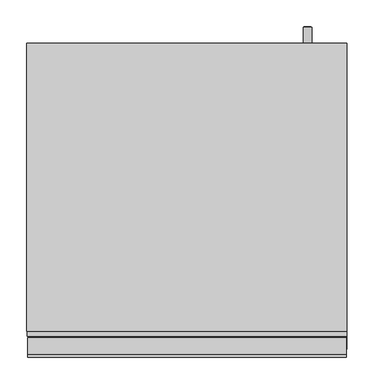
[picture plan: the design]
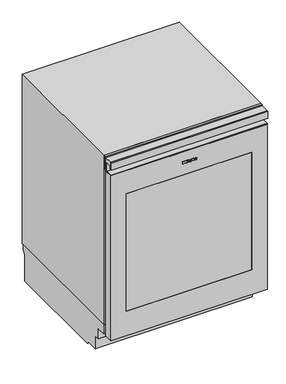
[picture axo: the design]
"""IFC4 building model written with IfcOpenShell, lengths in millimetres: proxy geometry."""

from ifc_helpers import new_model, si_unit, point, frame, frame_2d, origin, origin_with_axes, place, context, project, spatial, polyline, circle_curve, ellipse_curve, trimmed, segment, composite_curve, outline, extrude, faceted_brep, source, transform, mapped, element, save
from ifc_brep_helpers import plane_surface, cylinder_surface, revolved_surface, extruded_surface, advanced_brep


def specialty_equipment_ec8dbac2(model_context):
    return source(origin(), model_context, "Body", "SolidModel", [
        extrude(outline(polyline([(722.339, -25.038), (722.339, -23.949), (716.318, -23.949), (716.318, -25.038), (714.806, -25.038), (714.806, -21.078), (716.318, -21.078), (716.318, -22.158), (720.1401247, -22.158), (714.806, -18.135), (720.2462223, -14.094), (716.318, -14.094), (716.318, -15.201), (714.806, -15.201), (714.806, -8.019), (716.318, -8.019), (716.318, -9.162), (722.339, -9.162), (722.339, -8.019), (723.806, -8.019), (723.806, -13.5), (720.431, -16.128), (723.806, -18.765), (723.806, -25.038), (722.339, -25.038)])), frame((0.0, -1.0, 0.0), z_axis=(0.0, 1.0, 0.0), x_axis=(0.0, 0.0, 1.0)), (0.0, 0.0, 1.0), 1.0),
        extrude(outline(polyline([(722.339, 11.484), (722.339, 12.564), (716.318, 12.564), (716.318, 11.484), (714.806, 11.484), (714.806, 18.783), (716.318, 18.783), (716.318, 17.676), (723.806, 17.676), (723.806, 11.484), (722.339, 11.484)])), frame((0.0, -1.0, 0.0), z_axis=(0.0, 1.0, 0.0), x_axis=(0.0, 0.0, 1.0)), (0.0, 0.0, 1.0), 1.0),
        extrude(outline(polyline([(723.275, -4.878), (721.817, -4.194), (723.239, -1.143), (724.697, -1.818), (723.275, -4.878)])), frame((0.0, -1.0, 0.0), z_axis=(0.0, 1.0, 0.0), x_axis=(0.0, 0.0, 1.0)), (0.0, 0.0, 1.0), 1.0),
        extrude(outline(polyline([(721.619, -7.101), (720.008, -7.101), (720.008, -6.03), (716.318, -6.03), (716.318, -7.101), (714.806, -7.101), (714.806, 0.0), (716.318, 0.0), (716.318, -1.044), (721.619, -1.044), (721.619, -7.101)])), frame((0.0, -1.0, 0.0), z_axis=(0.0, 1.0, 0.0), x_axis=(0.0, 0.0, 1.0)), (0.0, 0.0, 1.0), 1.0),
        advanced_brep(
        [(4.959, -1.0, 716.939), (4.959, -1.0, 717.848), (10.98, -1.0, 717.848), (0.504, -1.0, 717.848), (2.979, -1.0, 714.806), (10.827, -1.0, 716.939), (8.109, -1.0, 716.939), (5.967, -1.0, 715.931), (4.959, -1.0, 719.0), (4.959, -1.0, 719.981), (6.498, -1.0, 719.981), (6.498, -1.0, 719.0), (4.959, 0.0, 716.939), (5.967, 0.0, 715.931), (8.109, 0.0, 716.939), (10.827, 0.0, 716.939), (2.979, 0.0, 714.806), (0.504, 0.0, 717.848), (10.98, 0.0, 717.848), (4.959, 0.0, 717.848), (4.959, 0.0, 719.0), (6.498, 0.0, 719.0), (6.498, 0.0, 719.981), (4.959, 0.0, 719.981)],
        [
            (0, 1),
            (1, 2),
            (2, 3, ellipse_curve(frame((5.742, -1.0, 717.848), z_axis=(0.0, -1.0, 0.0), x_axis=(-1.0, 0.0, 0.0)), 5.238, 4.329)),
            (3, 4, circle_curve(frame((3.9870491, -1.0, 718.154), z_axis=(0.0, -1.0, 0.0), x_axis=(0.0, 0.0, -1.0)), 3.4964649)),
            (4, 5, circle_curve(frame((5.6371428, -1.0, 720.53), z_axis=(0.0, -1.0, 0.0), x_axis=(0.0, 0.0, -1.0)), 6.3110933)),
            (5, 6),
            (6, 7, circle_curve(frame((6.4069412, -1.0, 717.776), z_axis=(0.0, 1.0, 0.0), x_axis=(0.0, 0.0, -1.0)), 1.896727)),
            (7, 0, circle_curve(frame((5.967, -1.0, 716.939), z_axis=(0.0, 1.0, 0.0), x_axis=(0.0, 0.0, -1.0)), 1.008)),
            (8, 9),
            (9, 10, circle_curve(frame((5.7285, -1.0, 719.981), z_axis=(0.0, 1.0, 0.0), x_axis=(0.0, 0.0, -1.0)), 0.7695)),
            (10, 11),
            (11, 8),
            (12, 13, circle_curve(frame((5.967, 0.0, 716.939), z_axis=(0.0, -1.0, 0.0), x_axis=(0.0, 0.0, -1.0)), 1.008)),
            (13, 14, circle_curve(frame((6.4069412, 0.0, 717.776), z_axis=(0.0, -1.0, 0.0), x_axis=(0.0, 0.0, -1.0)), 1.896727)),
            (14, 15),
            (15, 16, circle_curve(frame((5.6371428, 0.0, 720.53), z_axis=(0.0, 1.0, 0.0), x_axis=(0.0, 0.0, -1.0)), 6.3110933)),
            (16, 17, circle_curve(frame((3.9870491, 0.0, 718.154), z_axis=(0.0, 1.0, 0.0), x_axis=(0.0, 0.0, -1.0)), 3.4964649)),
            (17, 18, ellipse_curve(frame((5.742, 0.0, 717.848), z_axis=(0.0, 1.0, 0.0), x_axis=(-1.0, 0.0, 0.0)), 5.238, 4.329)),
            (18, 19),
            (19, 12),
            (20, 21),
            (21, 22),
            (22, 23, circle_curve(frame((5.7285, 0.0, 719.981), z_axis=(0.0, -1.0, 0.0), x_axis=(0.0, 0.0, -1.0)), 0.7695)),
            (23, 20),
            (0, 12),
            (19, 1),
            (18, 2),
            (5, 15),
            (14, 6),
            (17, 3),
            (13, 7),
            (16, 4),
            (8, 20),
            (23, 9),
            (22, 10),
            (21, 11),
        ],
        [
            plane_surface(frame((4.959, -1.0, 717.848), z_axis=(0.0, -1.0, 0.0), x_axis=(0.0, 0.0, 1.0))),
            plane_surface(frame((4.959, 0.0, 717.848), z_axis=(0.0, 1.0, 0.0), x_axis=(0.0, 0.0, -1.0))),
            plane_surface(frame((4.959, -1.0, 716.939), z_axis=(1.0, 0.0, 0.0), x_axis=(0.0, 1.0, 0.0))),
            plane_surface(frame((4.959, -1.0, 717.848), z_axis=(0.0, 0.0, -1.0), x_axis=(0.0, 1.0, 0.0))),
            plane_surface(frame((10.827, -1.0, 716.939), z_axis=(0.0, 0.0, 1.0), x_axis=(0.0, 1.0, 0.0))),
            extruded_surface(trimmed(ellipse_curve(frame((5.742, 1.0, 717.848), z_axis=(0.0, -1.0, 0.0), x_axis=(-1.0, 0.0, 0.0)), 5.238, 4.329), [point((10.98, 1.0, 717.848))], [point((0.504, 1.0, 717.848))], True, "CARTESIAN"), (0.0, -1.0, 0.0), 1.0),
            revolved_surface(polyline([(6.4069412, 0.0, 715.8792729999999), (6.4069412, -1.0, 715.8792729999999)]), (6.4069412, 0.0, 717.776), (0.0, 1.0, 0.0)),
            revolved_surface(polyline([(5.967, 0.0, 715.9309999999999), (5.967, -1.0, 715.9309999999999)]), (5.967, 0.0, 716.939), (0.0, 1.0, 0.0)),
            cylinder_surface(frame((3.9870491, 0.0, 718.154), z_axis=(0.0, -1.0, 0.0), x_axis=(0.0, 0.0, -1.0)), 3.4964649),
            cylinder_surface(frame((5.6371428, 0.0, 720.53), z_axis=(0.0, -1.0, 0.0), x_axis=(0.0, 0.0, -1.0)), 6.3110933),
            plane_surface(frame((4.959, -1.0, 719.0), z_axis=(1.0, 0.0, 0.0), x_axis=(0.0, 1.0, 0.0))),
            revolved_surface(polyline([(5.7285, 0.0, 719.2115), (5.7285, -1.0, 719.2115)]), (5.7285, 0.0, 719.981), (0.0, 1.0, 0.0)),
            plane_surface(frame((6.498, -1.0, 719.981), z_axis=(-1.0, 0.0, 0.0), x_axis=(0.0, 1.0, 0.0))),
            plane_surface(frame((6.498, -1.0, 719.0), z_axis=(0.0, 0.0, 1.0), x_axis=(0.0, 1.0, 0.0))),
        ],
        [
            (0, [[1, 2, 3, 4, 5, 6, 7, 8], [9, 10, 11, 12]]),
            (1, [[13, 14, 15, 16, 17, 18, 19, 20], [21, 22, 23, 24]]),
            (2, [[-1, 25, -20, 26]]),
            (3, [[-2, -26, -19, 27]]),
            (4, [[-6, 28, -15, 29]]),
            (5, [[-3, -27, -18, 30]]),
            (6, [[-7, -29, -14, 31]]),
            (7, [[-8, -31, -13, -25]]),
            (8, [[-4, -30, -17, 32]]),
            (9, [[-5, -32, -16, -28]]),
            (10, [[-9, 33, -24, 34]]),
            (11, [[-10, -34, -23, 35]]),
            (12, [[-11, -35, -22, 36]]),
            (13, [[-12, -36, -21, -33]]),
        ],
    ),
        advanced_brep(
        [(23.742, -1.0, 716.939), (23.742, -1.0, 717.848), (29.763, -1.0, 717.848), (19.287, -1.0, 717.848), (21.762, -1.0, 714.806), (29.61, -1.0, 716.939), (26.892, -1.0, 716.939), (24.75, -1.0, 715.931), (23.742, -1.0, 719.0), (23.742, -1.0, 719.981), (25.281, -1.0, 719.981), (25.281, -1.0, 719.0), (23.742, 0.0, 716.939), (24.75, 0.0, 715.931), (26.892, 0.0, 716.939), (29.61, 0.0, 716.939), (21.762, 0.0, 714.806), (19.287, 0.0, 717.848), (29.763, 0.0, 717.848), (23.742, 0.0, 717.848), (23.742, 0.0, 719.0), (25.281, 0.0, 719.0), (25.281, 0.0, 719.981), (23.742, 0.0, 719.981)],
        [
            (0, 1),
            (1, 2),
            (2, 3, ellipse_curve(frame((24.525, -1.0, 717.848), z_axis=(0.0, -1.0, 0.0), x_axis=(-1.0, 0.0, 0.0)), 5.238, 4.329)),
            (3, 4, circle_curve(frame((22.7700491, -1.0, 718.154), z_axis=(0.0, -1.0, 0.0), x_axis=(0.0, 0.0, -1.0)), 3.4964649)),
            (4, 5, circle_curve(frame((24.4201428, -1.0, 720.53), z_axis=(0.0, -1.0, 0.0), x_axis=(0.0, 0.0, -1.0)), 6.3110933)),
            (5, 6),
            (6, 7, circle_curve(frame((25.1899412, -1.0, 717.776), z_axis=(0.0, 1.0, 0.0), x_axis=(0.0, 0.0, -1.0)), 1.896727)),
            (7, 0, circle_curve(frame((24.75, -1.0, 716.939), z_axis=(0.0, 1.0, 0.0), x_axis=(0.0, 0.0, -1.0)), 1.008)),
            (8, 9),
            (9, 10, circle_curve(frame((24.5115, -1.0, 719.981), z_axis=(0.0, 1.0, 0.0), x_axis=(0.0, 0.0, -1.0)), 0.7695)),
            (10, 11),
            (11, 8),
            (12, 13, circle_curve(frame((24.75, 0.0, 716.939), z_axis=(0.0, -1.0, 0.0), x_axis=(0.0, 0.0, -1.0)), 1.008)),
            (13, 14, circle_curve(frame((25.1899412, 0.0, 717.776), z_axis=(0.0, -1.0, 0.0), x_axis=(0.0, 0.0, -1.0)), 1.896727)),
            (14, 15),
            (15, 16, circle_curve(frame((24.4201428, 0.0, 720.53), z_axis=(0.0, 1.0, 0.0), x_axis=(0.0, 0.0, -1.0)), 6.3110933)),
            (16, 17, circle_curve(frame((22.7700491, 0.0, 718.154), z_axis=(0.0, 1.0, 0.0), x_axis=(0.0, 0.0, -1.0)), 3.4964649)),
            (17, 18, ellipse_curve(frame((24.525, 0.0, 717.848), z_axis=(0.0, 1.0, 0.0), x_axis=(-1.0, 0.0, 0.0)), 5.238, 4.329)),
            (18, 19),
            (19, 12),
            (20, 21),
            (21, 22),
            (22, 23, circle_curve(frame((24.5115, 0.0, 719.981), z_axis=(0.0, -1.0, 0.0), x_axis=(0.0, 0.0, -1.0)), 0.7695)),
            (23, 20),
            (0, 12),
            (19, 1),
            (18, 2),
            (5, 15),
            (14, 6),
            (17, 3),
            (13, 7),
            (16, 4),
            (8, 20),
            (23, 9),
            (22, 10),
            (21, 11),
        ],
        [
            plane_surface(frame((23.742, -1.0, 717.848), z_axis=(0.0, -1.0, 0.0), x_axis=(0.0, 0.0, 1.0))),
            plane_surface(frame((23.742, 0.0, 717.848), z_axis=(0.0, 1.0, 0.0), x_axis=(0.0, 0.0, -1.0))),
            plane_surface(frame((23.742, -1.0, 716.939), z_axis=(1.0, 0.0, 0.0), x_axis=(0.0, 1.0, 0.0))),
            plane_surface(frame((23.742, -1.0, 717.848), z_axis=(0.0, 0.0, -1.0), x_axis=(0.0, 1.0, 0.0))),
            plane_surface(frame((29.61, -1.0, 716.939), z_axis=(0.0, 0.0, 1.0), x_axis=(0.0, 1.0, 0.0))),
            extruded_surface(trimmed(ellipse_curve(frame((24.525, 1.0, 717.848), z_axis=(0.0, -1.0, 0.0), x_axis=(-1.0, 0.0, 0.0)), 5.238, 4.329), [point((29.763, 1.0, 717.848))], [point((19.287, 1.0, 717.848))], True, "CARTESIAN"), (0.0, -1.0, 0.0), 1.0),
            revolved_surface(polyline([(25.1899412, 0.0, 715.8792729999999), (25.1899412, -1.0, 715.8792729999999)]), (25.1899412, 0.0, 717.776), (0.0, 1.0, 0.0)),
            revolved_surface(polyline([(24.75, 0.0, 715.9309999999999), (24.75, -1.0, 715.9309999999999)]), (24.75, 0.0, 716.939), (0.0, 1.0, 0.0)),
            cylinder_surface(frame((22.7700491, 0.0, 718.154), z_axis=(0.0, -1.0, 0.0), x_axis=(0.0, 0.0, -1.0)), 3.4964649),
            cylinder_surface(frame((24.4201428, 0.0, 720.53), z_axis=(0.0, -1.0, 0.0), x_axis=(0.0, 0.0, -1.0)), 6.3110933),
            plane_surface(frame((23.742, -1.0, 719.0), z_axis=(1.0, 0.0, 0.0), x_axis=(0.0, 1.0, 0.0))),
            revolved_surface(polyline([(24.5115, 0.0, 719.2115), (24.5115, -1.0, 719.2115)]), (24.5115, 0.0, 719.981), (0.0, 1.0, 0.0)),
            plane_surface(frame((25.281, -1.0, 719.981), z_axis=(-1.0, 0.0, 0.0), x_axis=(0.0, 1.0, 0.0))),
            plane_surface(frame((25.281, -1.0, 719.0), z_axis=(0.0, 0.0, 1.0), x_axis=(0.0, 1.0, 0.0))),
        ],
        [
            (0, [[1, 2, 3, 4, 5, 6, 7, 8], [9, 10, 11, 12]]),
            (1, [[13, 14, 15, 16, 17, 18, 19, 20], [21, 22, 23, 24]]),
            (2, [[-1, 25, -20, 26]]),
            (3, [[-2, -26, -19, 27]]),
            (4, [[-6, 28, -15, 29]]),
            (5, [[-3, -27, -18, 30]]),
            (6, [[-7, -29, -14, 31]]),
            (7, [[-8, -31, -13, -25]]),
            (8, [[-4, -30, -17, 32]]),
            (9, [[-5, -32, -16, -28]]),
            (10, [[-9, 33, -24, 34]]),
            (11, [[-10, -34, -23, 35]]),
            (12, [[-11, -35, -22, 36]]),
            (13, [[-12, -36, -21, -33]]),
        ],
    ),
        extrude(outline(polyline([(454.1556157, -89.367984), (454.1556157, -88.399984), (448.8036157, -88.399984), (448.8036157, -89.367984), (447.4596157, -89.367984), (447.4596157, -85.847984), (448.8036157, -85.847984), (448.8036157, -86.807984), (452.2067404, -86.807984), (447.4596157, -83.231984), (452.274838, -79.639984), (448.8036157, -79.639984), (448.8036157, -80.623984), (447.4596157, -80.623984), (447.4596157, -74.239984), (448.8036157, -74.239984), (448.8036157, -75.255984), (454.1556157, -75.255984), (454.1556157, -74.239984), (455.4596157, -74.239984), (455.4596157, -79.111984), (452.4596157, -81.447984), (455.4596157, -83.791984), (455.4596157, -89.367984), (454.1556157, -89.367984)])), frame((0.0, 50.0, 0.0), z_axis=(0.0, 1.0, 0.0), x_axis=(0.0, 0.0, 1.0)), (0.0, 0.0, 1.0), 1.0),
        extrude(outline(polyline([(454.1556157, -56.903984), (454.1556157, -55.943984), (448.8036157, -55.943984), (448.8036157, -56.903984), (447.4596157, -56.903984), (447.4596157, -50.415984), (448.8036157, -50.415984), (448.8036157, -51.399984), (455.4596157, -51.399984), (455.4596157, -56.903984), (454.1556157, -56.903984)])), frame((0.0, 50.0, 0.0), z_axis=(0.0, 1.0, 0.0), x_axis=(0.0, 0.0, 1.0)), (0.0, 0.0, 1.0), 1.0),
        extrude(outline(polyline([(454.9876157, -71.447984), (453.6916157, -70.839984), (454.9556157, -68.127984), (456.2516157, -68.727984), (454.9876157, -71.447984)])), frame((0.0, 50.0, 0.0), z_axis=(0.0, 1.0, 0.0), x_axis=(0.0, 0.0, 1.0)), (0.0, 0.0, 1.0), 1.0),
        extrude(outline(polyline([(453.5156157, -73.423984), (452.0836157, -73.423984), (452.0836157, -72.471984), (448.8036157, -72.471984), (448.8036157, -73.423984), (447.4596157, -73.423984), (447.4596157, -67.111984), (448.8036157, -67.111984), (448.8036157, -68.039984), (453.5156157, -68.039984), (453.5156157, -73.423984)])), frame((0.0, 50.0, 0.0), z_axis=(0.0, 1.0, 0.0), x_axis=(0.0, 0.0, 1.0)), (0.0, 0.0, 1.0), 1.0),
        advanced_brep(
        [(-62.703984, 50.0, 449.3556157), (-62.703984, 50.0, 450.1636157), (-57.351984, 50.0, 450.1636157), (-66.663984, 50.0, 450.1636157), (-64.463984, 50.0, 447.4596157), (-57.487984, 50.0, 449.3556157), (-59.903984, 50.0, 449.3556157), (-61.807984, 50.0, 448.4596157), (-62.703984, 50.0, 451.1876157), (-62.703984, 50.0, 452.0596157), (-61.335984, 50.0, 452.0596157), (-61.335984, 50.0, 451.1876157), (-62.703984, 51.0, 449.3556157), (-61.807984, 51.0, 448.4596157), (-59.903984, 51.0, 449.3556157), (-57.487984, 51.0, 449.3556157), (-64.463984, 51.0, 447.4596157), (-66.663984, 51.0, 450.1636157), (-57.351984, 51.0, 450.1636157), (-62.703984, 51.0, 450.1636157), (-62.703984, 51.0, 451.1876157), (-61.335984, 51.0, 451.1876157), (-61.335984, 51.0, 452.0596157), (-62.703984, 51.0, 452.0596157)],
        [
            (0, 1),
            (1, 2),
            (2, 3, ellipse_curve(frame((-62.007984, 50.0, 450.1636157), z_axis=(0.0, -1.0, 0.0), x_axis=(-1.0, 0.0, 0.0)), 4.656, 3.848)),
            (3, 4, circle_curve(frame((-63.5679404, 50.0, 450.4356157), z_axis=(0.0, -1.0, 0.0), x_axis=(0.0, 0.0, -1.0)), 3.1079688)),
            (4, 5, circle_curve(frame((-62.1011904, 50.0, 452.5476157), z_axis=(0.0, -1.0, 0.0), x_axis=(0.0, 0.0, -1.0)), 5.6098607)),
            (5, 6),
            (6, 7, circle_curve(frame((-61.4169252, 50.0, 450.0996157), z_axis=(0.0, 1.0, 0.0), x_axis=(0.0, 0.0, -1.0)), 1.6859795)),
            (7, 0, circle_curve(frame((-61.807984, 50.0, 449.3556157), z_axis=(0.0, 1.0, 0.0), x_axis=(0.0, 0.0, -1.0)), 0.896)),
            (8, 9),
            (9, 10, circle_curve(frame((-62.019984, 50.0, 452.0596157), z_axis=(0.0, 1.0, 0.0), x_axis=(0.0, 0.0, -1.0)), 0.684)),
            (10, 11),
            (11, 8),
            (12, 13, circle_curve(frame((-61.807984, 51.0, 449.3556157), z_axis=(0.0, -1.0, 0.0), x_axis=(0.0, 0.0, -1.0)), 0.896)),
            (13, 14, circle_curve(frame((-61.4169252, 51.0, 450.0996157), z_axis=(0.0, -1.0, 0.0), x_axis=(0.0, 0.0, -1.0)), 1.6859795)),
            (14, 15),
            (15, 16, circle_curve(frame((-62.1011904, 51.0, 452.5476157), z_axis=(0.0, 1.0, 0.0), x_axis=(0.0, 0.0, -1.0)), 5.6098607)),
            (16, 17, circle_curve(frame((-63.5679404, 51.0, 450.4356157), z_axis=(0.0, 1.0, 0.0), x_axis=(0.0, 0.0, -1.0)), 3.1079688)),
            (17, 18, ellipse_curve(frame((-62.007984, 51.0, 450.1636157), z_axis=(0.0, 1.0, 0.0), x_axis=(-1.0, 0.0, 0.0)), 4.656, 3.848)),
            (18, 19),
            (19, 12),
            (20, 21),
            (21, 22),
            (22, 23, circle_curve(frame((-62.019984, 51.0, 452.0596157), z_axis=(0.0, -1.0, 0.0), x_axis=(0.0, 0.0, -1.0)), 0.684)),
            (23, 20),
            (0, 12),
            (19, 1),
            (18, 2),
            (5, 15),
            (14, 6),
            (17, 3),
            (13, 7),
            (16, 4),
            (8, 20),
            (23, 9),
            (22, 10),
            (21, 11),
        ],
        [
            plane_surface(frame((-62.703984, 50.0, 450.1636157), z_axis=(0.0, -1.0, 0.0), x_axis=(0.0, 0.0, 1.0))),
            plane_surface(frame((-62.703984, 51.0, 450.1636157), z_axis=(0.0, 1.0, 0.0), x_axis=(0.0, 0.0, -1.0))),
            plane_surface(frame((-62.703984, 50.0, 449.3556157), z_axis=(1.0, 0.0, 0.0), x_axis=(0.0, 1.0, 0.0))),
            plane_surface(frame((-62.703984, 50.0, 450.1636157), z_axis=(0.0, 0.0, -1.0), x_axis=(0.0, 1.0, 0.0))),
            plane_surface(frame((-57.487984, 50.0, 449.3556157), z_axis=(0.0, 0.0, 1.0), x_axis=(0.0, 1.0, 0.0))),
            extruded_surface(trimmed(ellipse_curve(frame((-62.007984, 52.0, 450.1636157), z_axis=(0.0, -1.0, 0.0), x_axis=(-1.0, 0.0, 0.0)), 4.656, 3.848), [point((-57.351984, 52.0, 450.1636157))], [point((-66.663984, 52.0, 450.1636157))], True, "CARTESIAN"), (0.0, -1.0, 0.0), 1.0),
            revolved_surface(polyline([(-61.4169252, 51.0, 448.41363620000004), (-61.4169252, 50.0, 448.41363620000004)]), (-61.4169252, 51.0, 450.0996157), (0.0, 1.0, 0.0)),
            revolved_surface(polyline([(-61.807984, 51.0, 448.4596157), (-61.807984, 50.0, 448.4596157)]), (-61.807984, 51.0, 449.3556157), (0.0, 1.0, 0.0)),
            cylinder_surface(frame((-63.5679404, 51.0, 450.4356157), z_axis=(0.0, -1.0, 0.0), x_axis=(0.0, 0.0, -1.0)), 3.1079688),
            cylinder_surface(frame((-62.1011904, 51.0, 452.5476157), z_axis=(0.0, -1.0, 0.0), x_axis=(0.0, 0.0, -1.0)), 5.6098607),
            plane_surface(frame((-62.703984, 50.0, 451.1876157), z_axis=(1.0, 0.0, 0.0), x_axis=(0.0, 1.0, 0.0))),
            revolved_surface(polyline([(-62.019984, 51.0, 451.37561569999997), (-62.019984, 50.0, 451.37561569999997)]), (-62.019984, 51.0, 452.0596157), (0.0, 1.0, 0.0)),
            plane_surface(frame((-61.335984, 50.0, 452.0596157), z_axis=(-1.0, 0.0, 0.0), x_axis=(0.0, 1.0, 0.0))),
            plane_surface(frame((-61.335984, 50.0, 451.1876157), z_axis=(0.0, 0.0, 1.0), x_axis=(0.0, 1.0, 0.0))),
        ],
        [
            (0, [[1, 2, 3, 4, 5, 6, 7, 8], [9, 10, 11, 12]]),
            (1, [[13, 14, 15, 16, 17, 18, 19, 20], [21, 22, 23, 24]]),
            (2, [[-1, 25, -20, 26]]),
            (3, [[-2, -26, -19, 27]]),
            (4, [[-6, 28, -15, 29]]),
            (5, [[-3, -27, -18, 30]]),
            (6, [[-7, -29, -14, 31]]),
            (7, [[-8, -31, -13, -25]]),
            (8, [[-4, -30, -17, 32]]),
            (9, [[-5, -32, -16, -28]]),
            (10, [[-9, 33, -24, 34]]),
            (11, [[-10, -34, -23, 35]]),
            (12, [[-11, -35, -22, 36]]),
            (13, [[-12, -36, -21, -33]]),
        ],
    ),
        advanced_brep(
        [(-46.007984, 50.0, 449.3556157), (-46.007984, 50.0, 450.1636157), (-40.655984, 50.0, 450.1636157), (-49.967984, 50.0, 450.1636157), (-47.767984, 50.0, 447.4596157), (-40.791984, 50.0, 449.3556157), (-43.207984, 50.0, 449.3556157), (-45.111984, 50.0, 448.4596157), (-46.007984, 50.0, 451.1876157), (-46.007984, 50.0, 452.0596157), (-44.639984, 50.0, 452.0596157), (-44.639984, 50.0, 451.1876157), (-46.007984, 51.0, 449.3556157), (-45.111984, 51.0, 448.4596157), (-43.207984, 51.0, 449.3556157), (-40.791984, 51.0, 449.3556157), (-47.767984, 51.0, 447.4596157), (-49.967984, 51.0, 450.1636157), (-40.655984, 51.0, 450.1636157), (-46.007984, 51.0, 450.1636157), (-46.007984, 51.0, 451.1876157), (-44.639984, 51.0, 451.1876157), (-44.639984, 51.0, 452.0596157), (-46.007984, 51.0, 452.0596157)],
        [
            (0, 1),
            (1, 2),
            (2, 3, ellipse_curve(frame((-45.311984, 50.0, 450.1636157), z_axis=(0.0, -1.0, 0.0), x_axis=(-1.0, 0.0, 0.0)), 4.656, 3.848)),
            (3, 4, circle_curve(frame((-46.8719404, 50.0, 450.4356157), z_axis=(0.0, -1.0, 0.0), x_axis=(0.0, 0.0, -1.0)), 3.1079688)),
            (4, 5, circle_curve(frame((-45.4051904, 50.0, 452.5476157), z_axis=(0.0, -1.0, 0.0), x_axis=(0.0, 0.0, -1.0)), 5.6098607)),
            (5, 6),
            (6, 7, circle_curve(frame((-44.7209252, 50.0, 450.0996157), z_axis=(0.0, 1.0, 0.0), x_axis=(0.0, 0.0, -1.0)), 1.6859795)),
            (7, 0, circle_curve(frame((-45.111984, 50.0, 449.3556157), z_axis=(0.0, 1.0, 0.0), x_axis=(0.0, 0.0, -1.0)), 0.896)),
            (8, 9),
            (9, 10, circle_curve(frame((-45.323984, 50.0, 452.0596157), z_axis=(0.0, 1.0, 0.0), x_axis=(0.0, 0.0, -1.0)), 0.684)),
            (10, 11),
            (11, 8),
            (12, 13, circle_curve(frame((-45.111984, 51.0, 449.3556157), z_axis=(0.0, -1.0, 0.0), x_axis=(0.0, 0.0, -1.0)), 0.896)),
            (13, 14, circle_curve(frame((-44.7209252, 51.0, 450.0996157), z_axis=(0.0, -1.0, 0.0), x_axis=(0.0, 0.0, -1.0)), 1.6859795)),
            (14, 15),
            (15, 16, circle_curve(frame((-45.4051904, 51.0, 452.5476157), z_axis=(0.0, 1.0, 0.0), x_axis=(0.0, 0.0, -1.0)), 5.6098607)),
            (16, 17, circle_curve(frame((-46.8719404, 51.0, 450.4356157), z_axis=(0.0, 1.0, 0.0), x_axis=(0.0, 0.0, -1.0)), 3.1079688)),
            (17, 18, ellipse_curve(frame((-45.311984, 51.0, 450.1636157), z_axis=(0.0, 1.0, 0.0), x_axis=(-1.0, 0.0, 0.0)), 4.656, 3.848)),
            (18, 19),
            (19, 12),
            (20, 21),
            (21, 22),
            (22, 23, circle_curve(frame((-45.323984, 51.0, 452.0596157), z_axis=(0.0, -1.0, 0.0), x_axis=(0.0, 0.0, -1.0)), 0.684)),
            (23, 20),
            (0, 12),
            (19, 1),
            (18, 2),
            (5, 15),
            (14, 6),
            (17, 3),
            (13, 7),
            (16, 4),
            (8, 20),
            (23, 9),
            (22, 10),
            (21, 11),
        ],
        [
            plane_surface(frame((-46.007984, 50.0, 450.1636157), z_axis=(0.0, -1.0, 0.0), x_axis=(0.0, 0.0, 1.0))),
            plane_surface(frame((-46.007984, 51.0, 450.1636157), z_axis=(0.0, 1.0, 0.0), x_axis=(0.0, 0.0, -1.0))),
            plane_surface(frame((-46.007984, 50.0, 449.3556157), z_axis=(1.0, 0.0, 0.0), x_axis=(0.0, 1.0, 0.0))),
            plane_surface(frame((-46.007984, 50.0, 450.1636157), z_axis=(0.0, 0.0, -1.0), x_axis=(0.0, 1.0, 0.0))),
            plane_surface(frame((-40.791984, 50.0, 449.3556157), z_axis=(0.0, 0.0, 1.0), x_axis=(0.0, 1.0, 0.0))),
            extruded_surface(trimmed(ellipse_curve(frame((-45.311984, 52.0, 450.1636157), z_axis=(0.0, -1.0, 0.0), x_axis=(-1.0, 0.0, 0.0)), 4.656, 3.848), [point((-40.655984, 52.0, 450.1636157))], [point((-49.967984, 52.0, 450.1636157))], True, "CARTESIAN"), (0.0, -1.0, 0.0), 1.0),
            revolved_surface(polyline([(-44.7209252, 51.0, 448.41363620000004), (-44.7209252, 50.0, 448.41363620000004)]), (-44.7209252, 51.0, 450.0996157), (0.0, 1.0, 0.0)),
            revolved_surface(polyline([(-45.111984, 51.0, 448.4596157), (-45.111984, 50.0, 448.4596157)]), (-45.111984, 51.0, 449.3556157), (0.0, 1.0, 0.0)),
            cylinder_surface(frame((-46.8719404, 51.0, 450.4356157), z_axis=(0.0, -1.0, 0.0), x_axis=(0.0, 0.0, -1.0)), 3.1079688),
            cylinder_surface(frame((-45.4051904, 51.0, 452.5476157), z_axis=(0.0, -1.0, 0.0), x_axis=(0.0, 0.0, -1.0)), 5.6098607),
            plane_surface(frame((-46.007984, 50.0, 451.1876157), z_axis=(1.0, 0.0, 0.0), x_axis=(0.0, 1.0, 0.0))),
            revolved_surface(polyline([(-45.323984, 51.0, 451.37561569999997), (-45.323984, 50.0, 451.37561569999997)]), (-45.323984, 51.0, 452.0596157), (0.0, 1.0, 0.0)),
            plane_surface(frame((-44.639984, 50.0, 452.0596157), z_axis=(-1.0, 0.0, 0.0), x_axis=(0.0, 1.0, 0.0))),
            plane_surface(frame((-44.639984, 50.0, 451.1876157), z_axis=(0.0, 0.0, 1.0), x_axis=(0.0, 1.0, 0.0))),
        ],
        [
            (0, [[1, 2, 3, 4, 5, 6, 7, 8], [9, 10, 11, 12]]),
            (1, [[13, 14, 15, 16, 17, 18, 19, 20], [21, 22, 23, 24]]),
            (2, [[-1, 25, -20, 26]]),
            (3, [[-2, -26, -19, 27]]),
            (4, [[-6, 28, -15, 29]]),
            (5, [[-3, -27, -18, 30]]),
            (6, [[-7, -29, -14, 31]]),
            (7, [[-8, -31, -13, -25]]),
            (8, [[-4, -30, -17, 32]]),
            (9, [[-5, -32, -16, -28]]),
            (10, [[-9, 33, -24, 34]]),
            (11, [[-10, -34, -23, 35]]),
            (12, [[-11, -35, -22, 36]]),
            (13, [[-12, -36, -21, -33]]),
        ],
    ),
        extrude(outline(polyline([(238.8, -157.5), (243.5052612, -157.5), (247.5052612, -161.5), (247.5052612, -168.5), (243.5052612, -172.5), (238.8, -172.5), (238.8, -157.5)])), frame((0.0, 54.5000244, 0.0), z_axis=(0.0, 1.0, 0.0), x_axis=(0.0, 0.0, 1.0)), (0.0, 0.0, 1.0), 433.111792),
        extrude(outline(polyline([(238.8, -102.5), (243.5052612, -102.5), (247.5052612, -106.5), (247.5052612, -113.5), (243.5052612, -117.5), (238.8, -117.5), (238.8, -102.5)])), frame((0.0, 54.5000244, 0.0), z_axis=(0.0, 1.0, 0.0), x_axis=(0.0, 0.0, 1.0)), (0.0, 0.0, 1.0), 433.111792),
        extrude(outline(polyline([(238.8, 157.5), (238.8, 172.5), (243.5052612, 172.5), (247.5052612, 168.5), (247.5052612, 161.5), (243.5052612, 157.5), (238.8, 157.5)])), frame((0.0, 54.5000244, 0.0), z_axis=(0.0, 1.0, 0.0), x_axis=(0.0, 0.0, 1.0)), (0.0, 0.0, 1.0), 433.111792),
        extrude(outline(polyline([(238.8, 102.5), (238.8, 117.5), (243.5052612, 117.5), (247.5052612, 113.5), (247.5052612, 106.5), (243.5052612, 102.5), (238.8, 102.5)])), frame((0.0, 54.5000244, 0.0), z_axis=(0.0, 1.0, 0.0), x_axis=(0.0, 0.0, 1.0)), (0.0, 0.0, 1.0), 433.111792),
        extrude(outline(polyline([(238.8, -47.5), (243.5052612, -47.5), (247.5052612, -51.5), (247.5052612, -58.5), (243.5052612, -62.5), (238.8, -62.5), (238.8, -47.5)])), frame((0.0, 54.5000244, 0.0), z_axis=(0.0, 1.0, 0.0), x_axis=(0.0, 0.0, 1.0)), (0.0, 0.0, 1.0), 433.111792),
        extrude(outline(polyline([(238.8, 47.5), (238.8, 62.5), (243.5052612, 62.5), (247.5052612, 58.5), (247.5052612, 51.5), (243.5052612, 47.5), (238.8, 47.5)])), frame((0.0, 54.5000244, 0.0), z_axis=(0.0, 1.0, 0.0), x_axis=(0.0, 0.0, 1.0)), (0.0, 0.0, 1.0), 433.111792),
        extrude(outline(polyline([(238.8, 7.5), (243.5052612, 7.5), (247.5052612, 3.5), (247.5052612, -3.5), (243.5052612, -7.5), (238.8, -7.5), (238.8, 7.5)])), frame((0.0, 54.5000244, 0.0), z_axis=(0.0, 1.0, 0.0), x_axis=(0.0, 0.0, 1.0)), (0.0, 0.0, 1.0), 433.111792),
        extrude(outline(polyline([(238.5, 51.0000244), (-238.5, 51.0000244), (-238.5, 54.5000244), (238.5, 54.5000244), (238.5, 51.0000244)])), frame((0.0, 0.0, 146.0), z_axis=(0.0, 0.0, 1.0), x_axis=(1.0, 0.0, 0.0)), (0.0, 0.0, 1.0), 27.5),
        extrude(outline(polyline([(209.0, -226.9226475), (209.0, -238.5), (141.0206134, -238.5), (141.0206134, -216.8069153), (191.4790485, -216.8069153), (209.0, -226.9226475)])), frame((0.0, 54.5000244, 0.0), z_axis=(0.0, 1.0, 0.0), x_axis=(0.0, 0.0, 1.0)), (0.0, 0.0, 1.0), 308.1981801),
        extrude(outline(polyline([(209.0, 226.9226475), (191.4790485, 216.8069153), (141.0206134, 216.8069153), (141.0206134, 238.5), (209.0, 238.5), (209.0, 226.9226475)])), frame((0.0, 54.5000244, 0.0), z_axis=(0.0, 1.0, 0.0), x_axis=(0.0, 0.0, 1.0)), (0.0, 0.0, 1.0), 308.1981801),
        extrude(outline(polyline([(238.5, 51.0000244), (-238.5, 51.0000244), (-238.5, 54.5000244), (238.5, 54.5000244), (238.5, 51.0000244)])), frame((0.0, 0.0, 324.0), z_axis=(0.0, 0.0, 1.0), x_axis=(1.0, 0.0, 0.0)), (0.0, 0.0, 1.0), 27.5),
        extrude(outline(polyline([(618.2947388, -160.4764937), (623.0, -160.4764937), (627.0, -164.4764937), (627.0, -171.4764937), (623.0, -175.4764937), (618.2947388, -175.4764937), (618.2947388, -160.4764937)])), frame((0.0, 54.5000244, 0.0), z_axis=(0.0, 1.0, 0.0), x_axis=(0.0, 0.0, 1.0)), (0.0, 0.0, 1.0), 433.111792),
        extrude(outline(polyline([(618.2947388, -134.5453754), (623.0, -134.5453754), (627.0, -138.5453754), (627.0, -145.5453754), (623.0, -149.5453754), (618.2947388, -149.5453754), (618.2947388, -134.5453754)])), frame((0.0, 54.5000244, 0.0), z_axis=(0.0, 1.0, 0.0), x_axis=(0.0, 0.0, 1.0)), (0.0, 0.0, 1.0), 433.111792),
        extrude(outline(polyline([(618.2947388, -82.9166641), (623.0, -82.9166641), (627.0, -86.9166641), (627.0, -93.9166641), (623.0, -97.9166641), (618.2947388, -97.9166641), (618.2947388, -82.9166641)])), frame((0.0, 54.5000244, 0.0), z_axis=(0.0, 1.0, 0.0), x_axis=(0.0, 0.0, 1.0)), (0.0, 0.0, 1.0), 433.111792),
        extrude(outline(polyline([(618.2947388, -56.9855458), (623.0, -56.9855458), (627.0, -60.9855458), (627.0, -67.9855458), (623.0, -71.9855458), (618.2947388, -71.9855458), (618.2947388, -56.9855458)])), frame((0.0, 54.5000244, 0.0), z_axis=(0.0, 1.0, 0.0), x_axis=(0.0, 0.0, 1.0)), (0.0, 0.0, 1.0), 433.111792),
        extrude(outline(polyline([(618.2947388, 160.4764937), (618.2947388, 175.4764937), (623.0, 175.4764937), (627.0, 171.4764937), (627.0, 164.4764937), (623.0, 160.4764937), (618.2947388, 160.4764937)])), frame((0.0, 54.5000244, 0.0), z_axis=(0.0, 1.0, 0.0), x_axis=(0.0, 0.0, 1.0)), (0.0, 0.0, 1.0), 433.111792),
        extrude(outline(polyline([(618.2947388, 134.5453754), (618.2947388, 149.5453754), (623.0, 149.5453754), (627.0, 145.5453754), (627.0, 138.5453754), (623.0, 134.5453754), (618.2947388, 134.5453754)])), frame((0.0, 54.5000244, 0.0), z_axis=(0.0, 1.0, 0.0), x_axis=(0.0, 0.0, 1.0)), (0.0, 0.0, 1.0), 433.111792),
        extrude(outline(polyline([(618.2947388, 82.9166641), (618.2947388, 97.9166641), (623.0, 97.9166641), (627.0, 93.9166641), (627.0, 86.9166641), (623.0, 82.9166641), (618.2947388, 82.9166641)])), frame((0.0, 54.5000244, 0.0), z_axis=(0.0, 1.0, 0.0), x_axis=(0.0, 0.0, 1.0)), (0.0, 0.0, 1.0), 433.111792),
        extrude(outline(polyline([(618.2947388, 56.9855458), (618.2947388, 71.9855458), (623.0, 71.9855458), (627.0, 67.9855458), (627.0, 60.9855458), (623.0, 56.9855458), (618.2947388, 56.9855458)])), frame((0.0, 54.5000244, 0.0), z_axis=(0.0, 1.0, 0.0), x_axis=(0.0, 0.0, 1.0)), (0.0, 0.0, 1.0), 433.111792),
        extrude(outline(polyline([(618.2947388, -5.416666), (623.0, -5.416666), (627.0, -9.416666), (627.0, -16.416666), (623.0, -20.416666), (618.2947388, -20.416666), (618.2947388, -5.416666)])), frame((0.0, 54.5000244, 0.0), z_axis=(0.0, 1.0, 0.0), x_axis=(0.0, 0.0, 1.0)), (0.0, 0.0, 1.0), 433.111792),
        extrude(outline(polyline([(618.2947388, 20.5144523), (623.0, 20.5144523), (627.0, 16.5144523), (627.0, 9.5144523), (623.0, 5.5144523), (618.2947388, 5.5144523), (618.2947388, 20.5144523)])), frame((0.0, 54.5000244, 0.0), z_axis=(0.0, 1.0, 0.0), x_axis=(0.0, 0.0, 1.0)), (0.0, 0.0, 1.0), 433.111792),
        extrude(outline(polyline([(328.2947388, -160.4166718), (333.0, -160.4166718), (337.0, -164.4166718), (337.0, -171.4166718), (333.0, -175.4166718), (328.2947388, -175.4166718), (328.2947388, -160.4166718)])), frame((0.0, 54.5000244, 0.0), z_axis=(0.0, 1.0, 0.0), x_axis=(0.0, 0.0, 1.0)), (0.0, 0.0, 1.0), 433.111792),
        extrude(outline(polyline([(328.2947388, -134.4855535), (333.0, -134.4855535), (337.0, -138.4855535), (337.0, -145.4855535), (333.0, -149.4855535), (328.2947388, -149.4855535), (328.2947388, -134.4855535)])), frame((0.0, 54.5000244, 0.0), z_axis=(0.0, 1.0, 0.0), x_axis=(0.0, 0.0, 1.0)), (0.0, 0.0, 1.0), 433.111792),
        extrude(outline(polyline([(328.2947388, -82.8568422), (333.0, -82.8568422), (337.0, -86.8568422), (337.0, -93.8568422), (333.0, -97.8568422), (328.2947388, -97.8568422), (328.2947388, -82.8568422)])), frame((0.0, 54.5000244, 0.0), z_axis=(0.0, 1.0, 0.0), x_axis=(0.0, 0.0, 1.0)), (0.0, 0.0, 1.0), 433.111792),
        extrude(outline(polyline([(328.2947388, -56.9257239), (333.0, -56.9257239), (337.0, -60.9257239), (337.0, -67.9257239), (333.0, -71.9257239), (328.2947388, -71.9257239), (328.2947388, -56.9257239)])), frame((0.0, 54.5000244, 0.0), z_axis=(0.0, 1.0, 0.0), x_axis=(0.0, 0.0, 1.0)), (0.0, 0.0, 1.0), 433.111792),
        extrude(outline(polyline([(328.2947388, 160.5363156), (328.2947388, 175.5363156), (333.0, 175.5363156), (337.0, 171.5363156), (337.0, 164.5363156), (333.0, 160.5363156), (328.2947388, 160.5363156)])), frame((0.0, 54.5000244, 0.0), z_axis=(0.0, 1.0, 0.0), x_axis=(0.0, 0.0, 1.0)), (0.0, 0.0, 1.0), 433.111792),
        extrude(outline(polyline([(328.2947388, 134.6051973), (328.2947388, 149.6051973), (333.0, 149.6051973), (337.0, 145.6051973), (337.0, 138.6051973), (333.0, 134.6051973), (328.2947388, 134.6051973)])), frame((0.0, 54.5000244, 0.0), z_axis=(0.0, 1.0, 0.0), x_axis=(0.0, 0.0, 1.0)), (0.0, 0.0, 1.0), 433.111792),
        extrude(outline(polyline([(328.2947388, 82.976486), (328.2947388, 97.976486), (333.0, 97.976486), (337.0, 93.976486), (337.0, 86.976486), (333.0, 82.976486), (328.2947388, 82.976486)])), frame((0.0, 54.5000244, 0.0), z_axis=(0.0, 1.0, 0.0), x_axis=(0.0, 0.0, 1.0)), (0.0, 0.0, 1.0), 433.111792),
        extrude(outline(polyline([(328.2947388, 57.0453677), (328.2947388, 72.0453677), (333.0, 72.0453677), (337.0, 68.0453677), (337.0, 61.0453677), (333.0, 57.0453677), (328.2947388, 57.0453677)])), frame((0.0, 54.5000244, 0.0), z_axis=(0.0, 1.0, 0.0), x_axis=(0.0, 0.0, 1.0)), (0.0, 0.0, 1.0), 433.111792),
        extrude(outline(polyline([(328.2947388, -5.3568441), (333.0, -5.3568441), (337.0, -9.3568441), (337.0, -16.3568441), (333.0, -20.3568441), (328.2947388, -20.3568441), (328.2947388, -5.3568441)])), frame((0.0, 54.5000244, 0.0), z_axis=(0.0, 1.0, 0.0), x_axis=(0.0, 0.0, 1.0)), (0.0, 0.0, 1.0), 433.111792),
        extrude(outline(polyline([(328.2947388, 20.5742742), (333.0, 20.5742742), (337.0, 16.5742742), (337.0, 9.5742742), (333.0, 5.5742742), (328.2947388, 5.5742742), (328.2947388, 20.5742742)])), frame((0.0, 54.5000244, 0.0), z_axis=(0.0, 1.0, 0.0), x_axis=(0.0, 0.0, 1.0)), (0.0, 0.0, 1.0), 433.111792),
        extrude(outline(polyline([(238.5, 487.6118164), (-238.5, 487.6118164), (-238.5, 491.1118408), (238.5, 491.1118408), (238.5, 487.6118164)])), frame((0.0, 0.0, 235.0), z_axis=(0.0, 0.0, 1.0), x_axis=(1.0, 0.0, 0.0)), (0.0, 0.0, 1.0), 27.5),
        extrude(outline(polyline([(238.5, 51.0000244), (-238.5, 51.0000244), (-238.5, 54.5000244), (238.5, 54.5000244), (238.5, 51.0000244)])), frame((0.0, 0.0, 614.0), z_axis=(0.0, 0.0, 1.0), x_axis=(1.0, 0.0, 0.0)), (0.0, 0.0, 1.0), 27.5),
        extrude(outline(polyline([(238.5, 51.0000244), (-238.5, 51.0000244), (-238.5, 54.5000244), (238.5, 54.5000244), (238.5, 51.0000244)])), frame((0.0, 0.0, 235.0), z_axis=(0.0, 0.0, 1.0), x_axis=(1.0, 0.0, 0.0)), (0.0, 0.0, 1.0), 27.5),
        extrude(outline(polyline([(238.5, 487.6118164), (-238.5, 487.6118164), (-238.5, 491.1118408), (238.5, 491.1118408), (238.5, 487.6118164)])), frame((0.0, 0.0, 324.0), z_axis=(0.0, 0.0, 1.0), x_axis=(1.0, 0.0, 0.0)), (0.0, 0.0, 1.0), 27.5),
        extrude(outline(polyline([(238.5, 487.6118164), (-238.5, 487.6118164), (-238.5, 491.1118408), (238.5, 491.1118408), (238.5, 487.6118164)])), frame((0.0, 0.0, 614.0), z_axis=(0.0, 0.0, 1.0), x_axis=(1.0, 0.0, 0.0)), (0.0, 0.0, 1.0), 27.5),
        extrude(outline(polyline([(130.5000244, 149.7947388), (115.5000244, 149.7947388), (115.5000244, 154.5), (119.5000244, 158.5), (126.5000244, 158.5), (130.5000244, 154.5), (130.5000244, 149.7947388)])), frame((-216.555896, 0.0, 0.0), z_axis=(1.0, 0.0, 0.0), x_axis=(0.0, 1.0, 0.0)), (0.0, 0.0, 1.0), 433.111792),
        extrude(outline(polyline([(192.5000244, 149.7947388), (177.5000244, 149.7947388), (177.5000244, 154.5), (181.5000244, 158.5), (188.5000244, 158.5), (192.5000244, 154.5), (192.5000244, 149.7947388)])), frame((-216.555896, 0.0, 0.0), z_axis=(1.0, 0.0, 0.0), x_axis=(0.0, 1.0, 0.0)), (0.0, 0.0, 1.0), 433.111792),
        extrude(outline(polyline([(254.5000244, 149.7947388), (239.5000244, 149.7947388), (239.5000244, 154.5), (243.5000244, 158.5), (250.5000244, 158.5), (254.5000244, 154.5), (254.5000244, 149.7947388)])), frame((-216.555896, 0.0, 0.0), z_axis=(1.0, 0.0, 0.0), x_axis=(0.0, 1.0, 0.0)), (0.0, 0.0, 1.0), 433.111792),
        extrude(outline(polyline([(301.5000244, 149.7947388), (301.5000244, 154.5), (305.5000244, 158.5), (312.5000244, 158.5), (316.5000244, 154.5), (316.5000244, 149.7947388), (301.5000244, 149.7947388)])), frame((-216.555896, 0.0, 0.0), z_axis=(1.0, 0.0, 0.0), x_axis=(0.0, 1.0, 0.0)), (0.0, 0.0, 1.0), 433.111792),
        faceted_brep([(250.0, 48.6868019, 474.5), (-250.0, 48.6868019, 474.5), (-250.0, 48.6868019, 421.0838574), (250.0, 48.6868019, 421.0838574), (24.4663125, 48.6868019, 431.9573822), (-24.4663125, 48.6868019, 431.9573822), (-24.4663125, 48.6868019, 468.3698491), (24.4663125, 48.6868019, 468.3698491), (250.0, 487.6118164, 474.5), (250.0, 487.6118164, 421.0838574), (-250.0, 487.6118164, 421.0838574), (-250.0, 487.6118164, 474.5), (24.4663125, 188.5000244, 431.9573822), (24.4663125, 188.5000244, 468.3698491), (-24.4663125, 188.5000244, 468.3698491), (-24.4663125, 188.5000244, 431.9573822)], [[[0, 1, 2, 3], [4, 5, 6, 7]], [[8, 9, 10, 11]], [[1, 0, 8, 11]], [[2, 1, 11, 10]], [[3, 2, 10, 9]], [[0, 3, 9, 8]], [[12, 13, 14, 15]], [[12, 15, 5, 4]], [[15, 14, 6, 5]], [[14, 13, 7, 6]], [[13, 12, 4, 7]]]),
        extrude(outline(polyline([(24.4663125, 48.6868019), (-24.4663125, 48.6868019), (-24.4663125, 54.5000244), (24.4663125, 54.5000244), (24.4663125, 48.6868019)])), frame((0.0, 0.0, 431.9573822), z_axis=(0.0, 0.0, 1.0), x_axis=(1.0, 0.0, 0.0)), (0.0, 0.0, 1.0), 36.4124668),
        extrude(outline(polyline([(250.0, 48.6868019), (-250.0, 48.6868019), (-250.0, 487.6118164), (250.0, 487.6118164), (250.0, 48.6868019)])), frame((0.0, 0.0, 474.5), z_axis=(0.0, 0.0, 1.0), x_axis=(1.0, 0.0, 0.0)), (0.0, 0.0, 1.0), 12.0),
        extrude(outline(polyline([(238.5, 54.5000244), (219.7422474, 54.5000244), (219.7422474, 487.6118164), (238.5, 487.6118164), (238.5, 54.5000244)])), frame((0.0, 0.0, 324.0), z_axis=(0.0, 0.0, 1.0), x_axis=(1.0, 0.0, 0.0)), (0.0, 0.0, 1.0), 27.5),
        extrude(outline(polyline([(-219.7422474, 54.5000244), (-238.5, 54.5000244), (-238.5, 487.6118164), (-219.7422474, 487.6118164), (-219.7422474, 54.5000244)])), frame((0.0, 0.0, 324.0), z_axis=(0.0, 0.0, 1.0), x_axis=(1.0, 0.0, 0.0)), (0.0, 0.0, 1.0), 27.5),
        extrude(outline(polyline([(-219.7422474, 54.5000244), (-238.5, 54.5000244), (-238.5, 487.6118164), (-219.7422474, 487.6118164), (-219.7422474, 54.5000244)])), frame((0.0, 0.0, 235.0), z_axis=(0.0, 0.0, 1.0), x_axis=(1.0, 0.0, 0.0)), (0.0, 0.0, 1.0), 27.5),
        extrude(outline(polyline([(238.5, 54.5000244), (219.7422474, 54.5000244), (219.7422474, 487.6118164), (238.5, 487.6118164), (238.5, 54.5000244)])), frame((0.0, 0.0, 614.0), z_axis=(0.0, 0.0, 1.0), x_axis=(1.0, 0.0, 0.0)), (0.0, 0.0, 1.0), 27.5),
        extrude(outline(polyline([(-219.7422474, 54.5000244), (-238.5, 54.5000244), (-238.5, 487.6118164), (-219.7422474, 487.6118164), (-219.7422474, 54.5000244)])), frame((0.0, 0.0, 614.0), z_axis=(0.0, 0.0, 1.0), x_axis=(1.0, 0.0, 0.0)), (0.0, 0.0, 1.0), 27.5),
        extrude(outline(polyline([(238.5, 54.5000244), (219.7422474, 54.5000244), (219.7422474, 487.6118164), (238.5, 487.6118164), (238.5, 54.5000244)])), frame((0.0, 0.0, 235.0), z_axis=(0.0, 0.0, 1.0), x_axis=(1.0, 0.0, 0.0)), (0.0, 0.0, 1.0), 27.5),
        extrude(outline(polyline([(298.0, 34.0937347), (-298.0, 34.0937347), (-298.0, 44.0), (298.0, 44.0), (298.0, 34.0937347)])), frame((0.0, 0.0, 768.7051238), z_axis=(0.0, 0.0, 1.0), x_axis=(1.0, 0.0, 0.0)), (0.0, 0.0, 1.0), 48.9938508),
        faceted_brep([(-298.5, 573.5, 137.8999939), (-298.5, 573.5, 117.6051112), (-298.5, 561.0, 105.1051112), (-298.5, 561.0, 0.0), (-298.5, 150.9682763, 0.0), (-298.5, 142.6506717, 8.3176046), (-298.5, 100.0, 8.3176046), (-298.5, 100.0, 60.7725754), (-298.5, 79.0216446, 60.7725754), (-298.5, 79.0216446, 101.8184894), (-298.5, 44.0, 101.8184894), (-298.5, 44.0, 137.8999939), (298.5, 573.5, 137.8999939), (298.5, 44.0, 137.8999939), (298.5, 44.0, 101.8184894), (298.5, 79.0216446, 101.8184894), (298.5, 79.0216446, 60.7725754), (298.5, 100.0, 60.7725754), (298.5, 100.0, 8.3176046), (298.5, 142.6506717, 8.3176046), (298.5, 150.9682763, 0.0), (298.5, 561.0, 0.0), (298.5, 561.0, 105.1051112), (298.5, 573.5, 117.6051112), (296.7000122, 487.2596389, 0.0), (256.5957336, 487.2596389, 0.0), (256.5957336, 422.5975098, 0.0), (296.7000122, 422.5975098, 0.0), (-296.7000122, 487.2596389, 0.0), (-296.7000122, 422.5975098, 0.0), (-256.5957336, 422.5975098, 0.0), (-256.5957336, 487.2596389, 0.0), (296.7000122, 487.2596389, 8.7371401), (296.7000122, 422.5975098, 8.7371401), (256.5957336, 422.5975098, 8.7371401), (256.5957336, 487.2596389, 8.7371401), (-296.7000122, 487.2596389, 8.7371401), (-256.5957336, 487.2596389, 8.7371401), (-256.5957336, 422.5975098, 8.7371401), (-296.7000122, 422.5975098, 8.7371401)], [[[0, 1, 2, 3, 4, 5, 6, 7, 8, 9, 10, 11]], [[12, 13, 14, 15, 16, 17, 18, 19, 20, 21, 22, 23]], [[0, 11, 13, 12]], [[11, 10, 14, 13]], [[10, 9, 15, 14]], [[9, 8, 16, 15]], [[8, 7, 17, 16]], [[7, 6, 18, 17]], [[6, 5, 19, 18]], [[5, 4, 20, 19]], [[4, 3, 21, 20], [24, 25, 26, 27], [28, 29, 30, 31]], [[3, 2, 22, 21]], [[2, 1, 23, 22]], [[1, 0, 12, 23]], [[32, 33, 34, 35]], [[36, 37, 38, 39]], [[32, 35, 25, 24]], [[35, 34, 26, 25]], [[34, 33, 27, 26]], [[33, 32, 24, 27]], [[36, 39, 29, 28]], [[39, 38, 30, 29]], [[38, 37, 31, 30]], [[37, 36, 28, 31]]]),
        faceted_brep([(298.5, 44.0, 819.0), (298.5, 44.0, 137.8999939), (298.5, 579.6, 137.8999939), (298.5, 579.6, 819.0), (-298.5, 44.0, 819.0), (-298.5, 579.6, 819.0), (-298.5, 579.6, 137.8999939), (-298.5, 44.0, 137.8999939), (250.0, 44.0, 719.0), (250.0, 44.0, 150.0), (-250.0, 44.0, 150.0), (-250.0, 44.0, 719.0), (250.0, 534.2638012, 150.0), (250.0, 534.2638012, 719.0), (-250.0, 534.2638012, 719.0), (-250.0, 534.2638012, 150.0)], [[[0, 1, 2, 3]], [[4, 5, 6, 7]], [[1, 0, 4, 7], [8, 9, 10, 11]], [[2, 1, 7, 6]], [[3, 2, 6, 5]], [[0, 3, 5, 4]], [[12, 13, 14, 15]], [[13, 12, 9, 8]], [[14, 13, 8, 11]], [[15, 14, 11, 10]], [[12, 15, 10, 9]]]),
        extrude(outline(polyline([(250.0, 534.2638012), (250.0, 362.7), (-250.0, 362.7), (-250.0, 534.2638012), (250.0, 534.2638012)])), frame((0.0, 0.0, 150.0), z_axis=(0.0, 0.0, 1.0), x_axis=(1.0, 0.0, 0.0)), (0.0, 0.0, 1.0), 71.8999939),
        extrude(outline(composite_curve([segment(trimmed(circle_curve(frame_2d((-270.8532135, 135.87603)), 15.7049948), [point((-286.5582083, 135.87603))], [point((-255.1482187, 135.87603))], False, "CARTESIAN"), True, "CONTINUOUS"), segment(trimmed(circle_curve(frame_2d((-270.8532135, 135.87603)), 15.7049948), [point((-255.1482187, 135.87603))], [point((-286.5582083, 135.87603))], False, "CARTESIAN"), True, "CONTINUOUS")], self_intersect=False)), origin_with_axes(), (0.0, 0.0, 1.0), 8.3176046),
        extrude(outline(composite_curve([segment(trimmed(circle_curve(frame_2d((270.8532135, 135.87603)), 15.7049948), [point((286.5582083, 135.87603))], [point((255.1482187, 135.87603))], False, "CARTESIAN"), True, "CONTINUOUS"), segment(trimmed(circle_curve(frame_2d((270.8532135, 135.87603)), 15.7049948), [point((255.1482187, 135.87603))], [point((286.5582083, 135.87603))], False, "CARTESIAN"), True, "CONTINUOUS")], self_intersect=False)), origin_with_axes(), (0.0, 0.0, 1.0), 8.3176046),
        extrude(outline(composite_curve([segment(trimmed(circle_curve(frame_2d((-275.822369, 461.1385329)), 16.0), [point((-291.822369, 461.1385329))], [point((-259.822369, 461.1385329))], False, "CARTESIAN"), True, "CONTINUOUS"), segment(trimmed(circle_curve(frame_2d((-275.822369, 461.1385329)), 16.0), [point((-259.822369, 461.1385329))], [point((-291.822369, 461.1385329))], False, "CARTESIAN"), True, "CONTINUOUS")], self_intersect=False)), origin_with_axes(), (0.0, 0.0, 1.0), 8.3176046),
        extrude(outline(composite_curve([segment(trimmed(circle_curve(frame_2d((275.822369, 461.1385329)), 16.0), [point((259.822369, 461.1385329))], [point((291.822369, 461.1385329))], False, "CARTESIAN"), True, "CONTINUOUS"), segment(trimmed(circle_curve(frame_2d((275.822369, 461.1385329)), 16.0), [point((291.822369, 461.1385329))], [point((259.822369, 461.1385329))], False, "CARTESIAN"), True, "CONTINUOUS")], self_intersect=False)), origin_with_axes(), (0.0, 0.0, 1.0), 8.3176046),
        extrude(outline(composite_curve([segment(trimmed(circle_curve(frame_2d((144.2460785, 224.8152695)), 8.0), [point((144.2460785, 216.8152695))], [point((144.2460785, 232.8152695))], False, "CARTESIAN"), True, "CONTINUOUS"), segment(trimmed(circle_curve(frame_2d((144.2460785, 224.8152695)), 8.0), [point((144.2460785, 232.8152695))], [point((144.2460785, 216.8152695))], False, "CARTESIAN"), True, "CONTINUOUS")], self_intersect=False)), frame((0.0, 579.6, 0.0), z_axis=(0.0, 1.0, 0.0), x_axis=(0.0, 0.0, 1.0)), (0.0, 0.0, 1.0), 30.0),
        extrude(outline(polyline([(140.2460785, 230.7170777), (148.2825833, 230.7170777), (148.2825833, 224.9408399), (147.2780202, 224.9408399), (147.2780202, 229.7125146), (144.8921828, 229.7125146), (144.8921828, 225.1919806), (143.8876197, 225.1919806), (143.8876197, 229.7125146), (141.2506416, 229.7125146), (141.2506416, 224.8152695), (140.2460785, 224.8152695), (140.2460785, 230.7170777)])), frame((0.0, 609.6, 0.0), z_axis=(0.0, 1.0, 0.0), x_axis=(0.0, 0.0, 1.0)), (0.0, 0.0, 1.0), 1.0),
        extrude(outline(polyline([(140.2460785, 223.3084248), (148.2825833, 223.3084248), (148.2825833, 222.3038617), (141.2506416, 222.3038617), (141.2506416, 218.2856093), (140.2460785, 218.2856093), (140.2460785, 223.3084248)])), frame((0.0, 609.6, 0.0), z_axis=(0.0, 1.0, 0.0), x_axis=(0.0, 0.0, 1.0)), (0.0, 0.0, 1.0), 1.0),
        faceted_brep([(297.0, 0.0, 762.0), (-297.0, 0.0, 762.0), (-297.0, 0.0, 100.0), (297.0, 0.0, 100.0), (-238.0, 0.0, 670.0), (238.0, 0.0, 670.0), (238.0, 0.0, 198.0), (-238.0, 0.0, 198.0), (297.0, 32.0, 100.0), (-297.0, 32.0, 100.0), (-297.0, 32.0, 762.0), (297.0, 32.0, 762.0), (297.0, 32.0, 145.5520399), (190.2289267, 32.0, 145.5520399), (190.2289267, 32.0, 100.9715583), (297.0, 32.0, 100.9715583), (238.0, 32.0, 670.0), (-238.0, 32.0, 670.0), (-238.0, 32.0, 198.0), (238.0, 32.0, 198.0), (297.0, 10.6130013, 100.9715583), (297.0, 10.6130013, 145.5520399), (190.2289267, 10.6130013, 145.5520399), (190.2289267, 10.6130013, 100.9715583)], [[[0, 1, 2, 3], [4, 5, 6, 7]], [[8, 9, 10, 11, 12, 13, 14, 15], [16, 17, 18, 19]], [[1, 0, 11, 10]], [[2, 1, 10, 9]], [[3, 2, 9, 8]], [[0, 3, 8, 15, 20, 21, 12, 11]], [[16, 5, 4, 17]], [[17, 4, 7, 18]], [[18, 7, 6, 19]], [[5, 16, 19, 6]], [[21, 22, 13, 12]], [[14, 23, 20, 15]], [[23, 22, 21, 20]], [[22, 23, 14, 13]]]),
        extrude(outline(polyline([(764.5, 285.0), (764.5, -285.0), (148.5030441, -285.0), (148.5030441, 285.0), (764.5, 285.0)]), holes=[polyline([(670.0, -238.0), (670.0, 238.0), (198.0, 238.0), (198.0, -238.0), (670.0, -238.0)])]), frame((0.0, 32.0, 0.0), z_axis=(0.0, 1.0, 0.0), x_axis=(0.0, 0.0, 1.0)), (0.0, 0.0, 1.0), 12.0),
        extrude(outline(polyline([(297.0, 0.0), (297.0, -4.3999998), (-297.0, -4.3999998), (-297.0, 0.0), (297.0, 0.0)])), frame((0.0, 0.0, 787.8718872), z_axis=(0.0, 0.0, 1.0), x_axis=(1.0, 0.0, 0.0)), (0.0, 0.0, 1.0), 28.4282238),
        extrude(outline(polyline([(31.449995, 816.3006898), (31.449995, 762.0), (0.0, 762.0), (0.0, 764.3706666), (25.2610212, 764.3706666), (25.2610212, 799.0085449), (3.0130013, 799.0085449), (3.0130013, 787.161485), (0.0, 787.161485), (0.0, 816.3006898), (31.449995, 816.3006898)])), frame((-297.0, 0.0, 0.0), z_axis=(1.0, 0.0, 0.0), x_axis=(0.0, 1.0, 0.0)), (0.0, 0.0, 1.0), 594.0),
        extrude(outline(polyline([(238.0, 0.0), (-238.0, 0.0), (-238.0, 32.0), (238.0, 32.0), (238.0, 0.0)])), frame((0.0, 0.0, 197.9069346), z_axis=(0.0, 0.0, 1.0), x_axis=(1.0, 0.0, 0.0)), (0.0, 0.0, 1.0), 472.0930654),
        extrude(outline(polyline([(298.5, 10.6130013), (190.2289267, 10.6130013), (190.2289267, 44.0), (298.5, 44.0), (298.5, 10.6130013)])), frame((0.0, 0.0, 100.0), z_axis=(0.0, 0.0, 1.0), x_axis=(1.0, 0.0, 0.0)), (0.0, 0.0, 1.0), 41.0),
    ])


if __name__ == "__main__":
    model = new_model("IFC4")
    model_context = context("Model", 3, world=origin())
    ifc_project = project(units=[si_unit("LENGTHUNIT", "METRE", prefix="MILLI")], contexts=[model_context])
    site = spatial("IfcSite", under=ifc_project)
    building = spatial("IfcBuilding", under=site)
    placement = place(None, origin())
    specialty_equipment_shape = specialty_equipment_ec8dbac2(model_context)
    element("IfcBuildingElementProxy", 1, Name="Specialty Equipment", at=placement, inside=building, context=model_context, shape_type="MappedRepresentation", body=[
        mapped(specialty_equipment_shape, transform((0.0, 0.0, 0.0), x_axis=(1.0, 0.0, 0.0), y_axis=(0.0, 1.0, 0.0), z_axis=(0.0, 0.0, 1.0))),
    ])
    save(model, "model.ifc")
